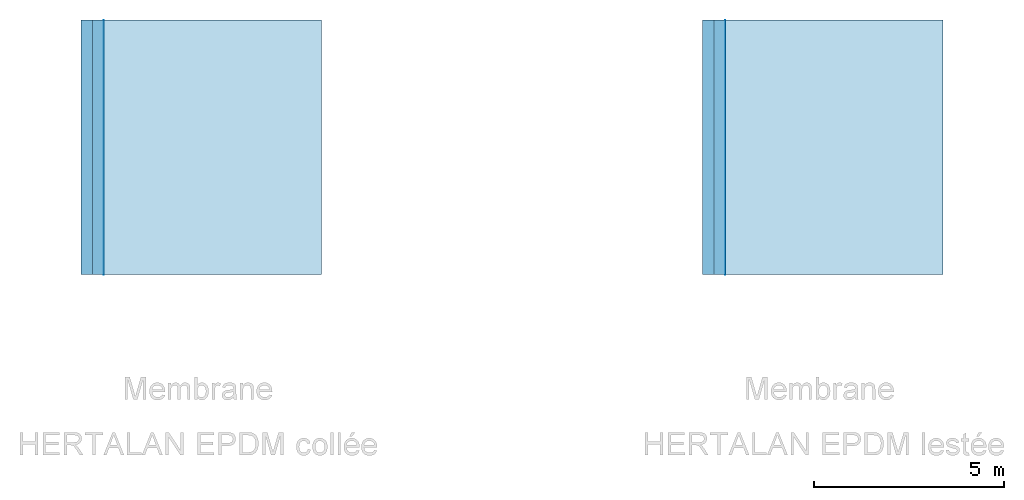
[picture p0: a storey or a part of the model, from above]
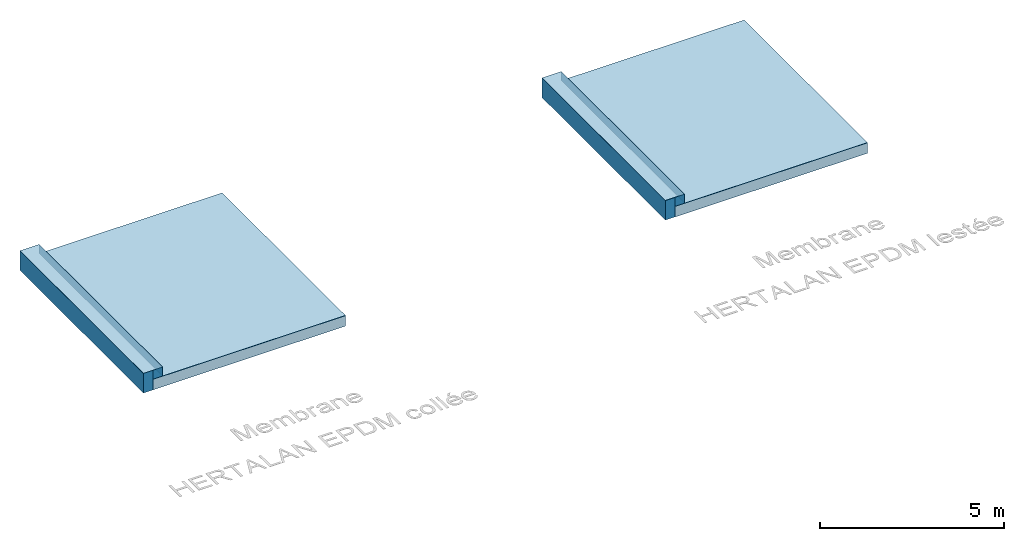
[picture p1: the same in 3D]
Properties of the parts of a building model (IFC2X3)

# File
Description: ViewDefinition [CoordinationView_V2.0, QuantityTakeOffAddOnView], RevitIdentifiers [ContentGUID: ba8bcfdc-dbaa-49fa-ac56-a6aa088a99af, VersionGUID: 4220247d-e962-4ae2-bb4a-8a5d9daa6820, NumberOfSaves: 104], CoordinateReference [CoordinateBase: Coordonnées partagées, ProjectSite: Interne]
File name: FR_Toit_VMBSO_HERTALAN_MEMBRANE_EPDM.ifc
Time: 2026-10-01T14:22:01+01:00
Written by: ODA SDAI 25.12
Made in: Autodesk - Revit 26.4.0.32 (FRA) - 26.4.0.32

# IfcSite, Default
RefLatitude: 42, 24, 53, 508911; RefLongitude: -71, -15, -29, -58837; RefElevation: 0 mm
Autre - Catégorie: Informations sur le projet

# IfcBuilding
Pset_BuildingCommon - NumberOfStoreys: 1
Autre - Catégorie: Informations sur le projet

# IfcBuildingStorey, Niveau 1
LongName: Niveau 1; Elevation: 0 mm
Autre - Catégorie: Niveaux; Famille: Niveau; Famille et type: Niveau: Niveau 1; ID du type: 1520; Type: Niveau 1
Contraintes - Elévation: 0 mm
Cotes - Hauteur de calcul: 0 mm
Données d'identification - Structure: no; Etage de bâtiment: yes; Nom: Niveau 1
Autre(Type) - Catégorie: Niveaux; Nom de la famille: Niveau
Contraintes(Type) - Référence de l'élévation: Point de base du projet
Graphismes(Type) - Couleur: 0; Epaisseur des lignes: 1; Motif des lignes: Plein; Valeur par défaut du symbole à l'extrémité 1: no; Valeur par défaut du symbole à l'extrémité 2: yes
Données d'identification(Type) - Nom du type: Niveau 1

# IfcBuildingElementProxy: Texte 3D:Model Text 1 (2)
In: Niveau 1
Type - Autre - Catégorie: Modèles génériques; Nom de la famille: Texte 3D
Type - Données d'identification - Nom du type: Model Text 1
Type - Texte - Gras: no; Italique: no; Police de texte: Arial; Taille du texte: 600 mm
Pset_BuildingElementProxyCommon - Reference: Model Text 1; sets with these values: 2
Autre - Famille: Texte 3D; Famille et type: Texte 3D: Model Text 1; ID du type: 2370; Type: Model Text 1
Contraintes - Plan de construction: <non associé>
Cotes - Profondeur: 10 mm
Graphismes - Alignement horizontal: Centre
Données d'identification - Sous-catégorie: Modèles génériques
Phase de construction - Phase de création: Nouvelle construction
Name (Texte 3D:Model Text 1:...) | Texte
24701 | Membrane HERTALAN EPDM collée
24706 | Membrane HERTALAN EPDM lestée

# IfcRoof (6)
In: Niveau 1
Pset_RoofCommon - IsExternal: yes
Autre - Catégorie: Toits; Famille: Toit de base
Contraintes - Décalage de la coupure: 0 mm; Lié au volume: no; Limite de pièce: yes; Niveau de base: Niveau 1
Construction - Coupe en chevron: Coupe verticale; Profondeur du bord de toiture: 0 mm
Phase de construction - Phase de création: Nouvelle construction
Name (Toit de base:...) | Material | Pset_QuantityTakeOff, Reference = Pset_RoofCommon, Reference = Type | ProjectedArea (m2) = TotalArea (m2) = GrossArea (m2) = NetArea (m2) = Surface (m2) | Famille et type | ID du type | Décalage inférieur à partir du niveau (mm) | Hauteur maximale de l'arrête (mm) | Epaisseur (mm) | Volume (m3)
Membrane Hertalan EPDM Partie courante collée:25614 | Membrane Hertalan EPDM collée_Partie courante 1.2 mm, Adhésif de contact 1.1 mm | Membrane Hertalan EPDM Partie courante collée | 38.5877 | Toit de base: Membrane Hertalan EPDM Partie courante collée | 13271 | 135.2 | 137.5 | 2.3 | 0.0887517 | Cotes - Inclinaison: 0
Membrane Hertalan EPDM Partie courante lestée:26349 | Film de protection polyester 0.8 mm, Membrane Hertalan EPDM lestée_Partie courante 1.5 mm | Membrane Hertalan EPDM Partie courante lestée | 38.5877 | Toit de base: Membrane Hertalan EPDM Partie courante lestée | 23930 | 135.2 | 137.5 | 2.3 | 0.0887517 | Cotes - Inclinaison: 0
Membrane Hertalan EPDM_Acrotère:31611 | Membrane Hertalan EPDM collée_Acrotère/Relevé 1.5 mm, Adhésif de contact 1.1 mm | Membrane Hertalan EPDM_Acrotère | 4.05083 | Toit de base: Membrane Hertalan EPDM_Acrotère | 19271 | 435.2 | 437.8 | 2.6 | 0.0105322 | Pset_ManufacturerTypeInformation - Manufacturer: VM BUILDING SOLUTIONS
Toit-Support autorisé:31936 | Isolation 100 mm, Pare vapeur 0.8 mm, Béton de pente 50 mm, Structure porteuse 200 mm | Toit-Support autorisé | 40.602 | Toit de base: Toit-Support autorisé | 31943 | -215.6 | 135.2 | 350.8 | 14.2432
Toit-Support autorisé:32010 | Isolation 100 mm, Pare vapeur 0.8 mm, Béton de pente 50 mm, Structure porteuse 200 mm | Toit-Support autorisé | 40.602 | Toit de base: Toit-Support autorisé | 31943 | -215.6 | 135.2 | 350.8 | 14.2432
Membrane Hertalan EPDM_Acrotère:32271 | Membrane Hertalan EPDM collée_Acrotère/Relevé 1.5 mm, Adhésif de contact 1.1 mm | Membrane Hertalan EPDM_Acrotère | 4.05083 | Toit de base: Membrane Hertalan EPDM_Acrotère | 19271 | 435.2 | 437.8 | 2.6 | 0.0105322 | Pset_ManufacturerTypeInformation - Manufacturer: VM BUILDING SOLUTIONS

# IfcSlab: Toit de base:Membrane Hertalan EPDM Partie courante collée, Toit de base:Membrane Hertalan EPDM Partie courante collée:25614
In: Niveau 1
Type - PredefinedType: ROOF
Type - Autre - Catégorie: Toits; Nom de la famille: Toit de base
Type - Construction - Climat: Zones de vent 1 à 4 (hors zone 5 et DROM)-Climat de plaine.; Conditions particulières: De faible à moyenne sur support bois. De faible à forte sur maçonnerie. Faible à très forte hygrométrie sur tôle d'acier nervurée.; Document de référence: DTA n°5.2/17-2578_V2, CCT Hertalan visé par Alpha Contrôle – Avril 2017; Epaisseur: 1,2 mm - 1,5 mm - 2,0 mm; Epaisseur par défaut: 2.3 mm; Masse surfacique: 1,47 kg/m² (1,2mm) - 1,84 kg/m² (1,5mm) - 2,46 kg/m² (2,0mm); Mise en œuvre: En adhérence totale ou partielle, existe en version pre-tape et en fixation mécanique; N° DTU: DTU de la série 43; Résistance au feu: Classe E Norme d'essai; Supports autorisés: Maçonnerie, Béton cellulaire, Bois et dérivés du bois, Isolation (laine minérale soudable, perlite expansée soudable, verre cellulaire, PIR, PUR, polystyrène…), Anciennes membranes bitumineuses; Type de toit: Nouvelle construction et rénovation, toiture accessible, technique ou non accessible de pente conforme à la norme NF P 84 série 200 (DTU série 43)
Type - Graphismes - Couleur vue détail faible: 0
Type - Données d'identification - Code Produit: E788; Commentaires du type: Membrane Hertalan EPDM collé; Description: Hertalan est une membrane EPDM non renforcée. Gamme moyenne.; Fournisseur: VM Building Solutions; Identifiant du type: Hertalan; Modèle: Membrane Hertalan EPDM collé; Nom du type: Membrane Hertalan EPDM Partie courante collée; URL: https://www.vmbuildingsolutions.com/fr-fr/epdm/membrane-epdm-hertalan
Type - Matériaux et finitions - Matériau principal: Membrane EPDM caoutchouc Hertalan
Type - Propriétés analytiques - Coefficient d'absorbance: 0.1; Rugosité: 1
Type - Pset_ReinforcementBarPitchOfSlab - Description: Hertalan est une membrane EPDM non renforcée. Gamme moyenne.
Material: Membrane Hertalan EPDM collée_Partie courante 1.2 mm, Adhésif de contact 1.1 mm
Pset_QuantityTakeOff - Reference: Membrane Hertalan EPDM Partie courante collée; sets with these values: 2
Pset_SlabCommon - Reference: Membrane Hertalan EPDM Partie courante collée; IsExternal: yes; PitchAngle: 0 deg
BaseQuantities - NetArea: 3.58491 m2; NetVolume: 0.0082453 m3; GrossArea: 38.5877 m2; GrossVolume: 0.0082453 m3; Perimeter: 24922.8 mm

# IfcSlab: Toit de base:Membrane Hertalan EPDM Partie courante lestée, Toit de base:Membrane Hertalan EPDM Partie courante lestée:26349
In: Niveau 1
Type - PredefinedType: ROOF
Type - Autre - Catégorie: Toits; Nom de la famille: Toit de base
Type - Construction - Conditions particulières: De faible à moyenne sur support bois. De faible à forte sur maçonnerie. Faible à très forte hygrométrie sur tôle d'acier nervurée.; Document de référence: DTA n°5.2/17-2578_V2, CCT Hertalan visé par Alpha Contrôle – Avril 2017; Epaisseur: 1,2 mm - 1,5 mm - 2,0 mm; Epaisseur par défaut: 2.3 mm; Masse surfacique: 1,47 kg/m² (1,2mm) - 1,84 kg/m² (1,5mm) - 2,46 kg/m² (2,0mm); Mise en œuvre: Adhérence totale ou partielle ou installation libre sous le lestage; N° DTU: DTU de la série 43; Résistance au feu: Classe E Norme d'essai; Supports autorisés: Maçonnerie, Béton cellulaire, Bois et dérivés du bois, Isolation (laine minérale soudable, perlite expansée soudable, verre cellulaire, PIR, PUR, polystyrène…), Anciennes membranes bitumineuses; Type de toit: Nouvelle construction et rénovation, toiture accessible, technique ou non accessible de pente conforme à la norme NF P 84 série 200 (DTU série 43), ou avis technique du support. En construction neuve ou en rénovation
Type - Graphismes - Couleur vue détail faible: 0
Type - Données d'identification - Code Produit: E788; Commentaires du type: Membrane EPDM Hertalan lestée; Description: Hertalan est une membrane EPDM non renforcée. Gamme moyenne.; Fournisseur: VM Building Solutions; Identifiant du type: Hertalan; Modèle: Membrane EPDM Hertalan lestée; Nom du type: Membrane Hertalan EPDM Partie courante lestée; URL: https://www.vmbuildingsolutions.com/fr-fr/epdm/membrane-epdm-hertalan
Type - Matériaux et finitions - Matériau principal: Membrane EPDM caoutchouc Hertalan
Type - Propriétés analytiques - Coefficient d'absorbance: 0.1; Rugosité: 1
Type - Pset_ReinforcementBarPitchOfSlab - Description: Hertalan est une membrane EPDM non renforcée. Gamme moyenne.
Material: Film de protection polyester 0.8 mm, Membrane Hertalan EPDM lestée_Partie courante 1.5 mm
Pset_QuantityTakeOff - Reference: Membrane Hertalan EPDM Partie courante lestée; sets with these values: 2
Pset_SlabCommon - IsExternal: yes; PitchAngle: 0 deg; Reference: Membrane Hertalan EPDM Partie courante lestée
BaseQuantities - NetArea: 3.58491 m2; NetVolume: 0.0082453 m3; GrossArea: 38.5877 m2; GrossVolume: 0.0082453 m3; Perimeter: 24922.8 mm

# IfcSlab: Toit de base:Membrane Hertalan EPDM_Acrotère (2)
In: Niveau 1
Type - PredefinedType: ROOF
Type - Autre - Catégorie: Toits; Nom de la famille: Toit de base
Type - Construction - Conditions particulières: De faible à moyenne sur support bois. De faible à forte sur maçonnerie. Faible à très forte hygrométrie sur tôle d'acier nervurée.; Document de référence: DTA n°5.2/17-2578_V2, CCT Hertalan visé par Alpha Contrôle – Avril 2017; Epaisseur: 1,2 mm - 1,5 mm - 2,0 mm; Epaisseur par défaut: 2.6 mm; Masse surfacique: 1,47 kg/m² (1,2mm) _ 1,84 kg/m² (1,5mm) _ 2,46 kg/m² (2,0mm); Mise en œuvre: Adhérence totale ou partielle ou installation libre sous le lestage; N° DTU: DTU de la série 43; Supports autorisés: Maçonnerie, Béton cellulaire, Bois et dérivés du bois, Isolation (laine minérale soudable (1), perlite expansée soudable (2), verre cellulaire, PIR, PUR, polystyrène…), Anciennes membranes bitumineuses; Type de toit: Nouvelle construction et rénovation, toiture accessible, technique ou non accessible de pente conforme à la norme NF P 84 série 200 (DTU série 43)
Type - Graphismes - Couleur vue détail faible: 0
Type - Données d'identification - Description: Hertalan est une membrane EPDM non renforcée. Gamme moyenne. Hertalan flashing – Bande EPDM non vulcanisée autoadhésive déformable pour finitions. Coins intérieur et extérieur Hertalan préfabriqués. Colles KS 137, KS 143, KS 205 et KS 96; Fabricant: VM BUILDING SOLUTIONS; Fournisseur: VM Building Solutions; Identifiant du type: Hertalan; Modèle: Membrane Hertalan EPDM collé; Nom du type: Membrane Hertalan EPDM_Acrotère; Note d'identification: Membrane Hertalan EPDM collée; URL: https://www.vmbuildingsolutions.com/fr-fr/epdm/membrane-epdm-hertalan
Type - Matériaux et finitions - Matériau principal: Membrane EPDM caoutchouc Hertalan
Type - Propriétés analytiques - Coefficient d'absorbance: 0.1; Rugosité: 1
Type - Pset_ManufacturerTypeInformation - Manufacturer: VM BUILDING SOLUTIONS
Type - Pset_ReinforcementBarPitchOfSlab - Description: Hertalan est une membrane EPDM non renforcée. Gamme moyenne. Hertalan flashing – Bande EPDM non vulcanisée autoadhésive déformable pour finitions. Coins intérieur et extérieur Hertalan préfabriqués. Colles KS 137, KS 143, KS 205 et KS 96
Material: Membrane Hertalan EPDM collée_Acrotère/Relevé 1.5 mm, Adhésif de contact 1.1 mm
Pset_QuantityTakeOff - Reference: Membrane Hertalan EPDM_Acrotère; sets with these values: 2
Pset_SlabCommon - IsExternal: yes; PitchAngle: 0 deg; Reference: Membrane Hertalan EPDM_Acrotère
BaseQuantities - NetArea: 0.376335 m2; NetVolume: 0.000978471 m3; GrossArea: 4.05083 m2; GrossVolume: 0.000978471 m3; Perimeter: 14635.5 mm
Name (Toit de base:Membrane Hertalan EPDM_Acrotère:...)
31611
32271

# IfcSlab: Toit de base:Toit-Support autorisé (2)
In: Niveau 1
Type - PredefinedType: ROOF
Type - Autre - Catégorie: Toits; Nom de la famille: Toit de base
Type - Construction - Epaisseur par défaut: 350.8 mm
Type - Graphismes - Couleur vue détail faible: 0
Type - Données d'identification - Nom du type: Toit-Support autorisé
Type - Propriétés analytiques - Coefficient d'absorbance: 0.1; Rugosité: 1
Material: Isolation 100 mm, Pare vapeur 0.8 mm, Béton de pente 50 mm, Structure porteuse 200 mm
Pset_QuantityTakeOff - Reference: Toit-Support autorisé; sets with these values: 2
Pset_SlabCommon - IsExternal: yes; PitchAngle: 0 deg; Reference: Toit-Support autorisé
BaseQuantities - NetArea: 3.77205 m2; NetVolume: 1.32324 m3; GrossArea: 40.602 m2; GrossVolume: 1.32324 m3; Perimeter: 25522.8 mm
Name (Toit de base:Toit-Support autorisé:...)
31936
32010

# IfcWallStandardCase: Mur de base:Membrane Hertalan EPDM Relevé collé (2)
In: Niveau 1
Type - PredefinedType: STANDARD; Material: Membrane Hertalan EPDM collée_Acrotère/Relevé 1.5 mm, Adhésif de contact 1.1 mm
Type - Autre - Catégorie: Murs; Nom de la famille: Mur de base
Type - Construction - Fonction: Extérieur; Retournement aux extrémités: Aucun(e); Retournement aux insertions: Ne pas retourner; Climat: Zones de vent 1 à 4 (hors zone 5 et DROM)-Climat de plaine.; Conditions particulières: Adhérence totale; Largeur: 2.6 mm; Mise en œuvre: Le relevé est entièrement recouvert de Hertalan collé à l'aide de l'adhésif de contact KS137 ou KS205.; N° DTU: DTU de la série 43; Supports autorisés: Maçonnerie, Béton cellulaire, Bois et dérivés du bois, Isolation (laine minérale soudable (1), perlite expansée soudable (2), verre cellulaire, PIR, PUR, polystyrène…), Anciennes membranes bitumineuses; Type de toit: Nouvelle construction et rénovation, toiture accessible, technique ou non accessible de pente conforme à la norme NF P 84 série 200 (DTU série 43)
Type - Graphismes - Couleur vue détail faible: 0
Type - Données d'identification - Commentaires du type: Membrane EPDM Hertalan collé; Description: Mise en place rapide sans plis. Très haute résistance constante aux UV. 100 % étanche pendant 50 ans. Pose sans flamme Très haute résistance constante aux UV 100 % étanche pendant 50 ans Pose sans flamme; Fournisseur: VM Building Solutions; Identifiant du type: Hertalan; Modèle: Membrane EPDM Hertalan collé; Nom du type: Membrane Hertalan EPDM Relevé collé; URL: https://www.vmbuildingsolutions.com/fr-fr/epdm/membrane-epdm-hertalan
Type - Matériaux et finitions - Matériau principal: Membrane EPDM caoutchouc Hertalan
Type - Propriétés analytiques - Coefficient d'absorbance: 0.1; Rugosité: 1
Type - Pset_ReinforcementBarPitchOfWall - Description: Mise en place rapide sans plis. Très haute résistance constante aux UV. 100 % étanche pendant 50 ans. Pose sans flamme Très haute résistance constante aux UV 100 % étanche pendant 50 ans Pose sans flamme
BaseQuantities - Length: 6714.46 mm; Width: 2.6 mm; GrossFootprintArea: 0.0174576 m2
Pset_QuantityTakeOff - Reference: Membrane Hertalan EPDM Relevé collé; sets with these values: 2
Pset_WallCommon - IsExternal: yes; ExtendToStructure: no; LoadBearing: no; Reference: Membrane Hertalan EPDM Relevé collé
Autre - Famille: Mur de base; Famille et type: Mur de base: Membrane Hertalan EPDM Relevé collé; ID du type: 2373; Type: Membrane Hertalan EPDM Relevé collé
Contraintes - Lié au volume: no; Limite de pièce: yes; Contrainte inférieure: Niveau 1; Décalage supérieur: 0 mm; Extension inférieure: 0 mm; Extension supérieure: 0 mm; Ligne de justification: Axe du mur; Partie inférieure attachée: no; Partie supérieure attachée: no
Cotes - Longueur: 6714.46 mm
Phase de construction - Phase de création: Nouvelle construction
Structure - Structure: no; Utilisation structurelle: Non porteur
Définition de la coupe transversale - Coupe transversale: Vertical
Name (Mur de base:Membrane Hertalan EPDM Relevé collé:...) | Height (mm) | GrossVolume (m3) = NetVolume (m3) = Volume (m3) | GrossSideArea (m2) = NetSideArea (m2) = Surface (m2) | Décalage inférieur (mm) | Hauteur non contrainte (mm)
25628 | 296.7 | 0.00517967 | 1.99218 | 138.5 | 161.5
26363 | 297 | 0.00518491 | 1.9942 | 178.665 | 121.335

# IfcWallStandardCase: Mur de base:Mur 1 (4)
In: Niveau 1
Type - PredefinedType: STANDARD; Material: Isolation 100 mm, Maçonnerie ascendante 200 mm
Type - Autre - Catégorie: Murs; Nom de la famille: Mur de base
Type - Construction - Fonction: Extérieur; Largeur: 300 mm; Retournement aux extrémités: Aucun(e); Retournement aux insertions: Ne pas retourner
Type - Graphismes - Couleur vue détail faible: 0
Type - Données d'identification - Nom du type: Mur 1
Type - Propriétés analytiques - Coefficient d'absorbance: 0.1; Rugosité: 1
BaseQuantities - Length: 6714.46 mm; Width: 300 mm; GrossFootprintArea: 2.01434 m2
Pset_QuantityTakeOff - Reference: Mur 1; sets with these values: 2
Pset_WallCommon - IsExternal: yes; Reference: Mur 1; ExtendToStructure: no; LoadBearing: no
Autre - Famille: Mur de base; Famille et type: Mur de base: Mur 1; ID du type: 1557; Type: Mur 1
Contraintes - Lié au volume: no; Limite de pièce: yes; Contrainte inférieure: Niveau 1; Décalage supérieur: 0 mm; Extension inférieure: 0 mm; Extension supérieure: 0 mm; Ligne de justification: Axe du mur; Partie inférieure attachée: no; Partie supérieure attachée: no
Cotes - Longueur: 6714.46 mm
Phase de construction - Phase de création: Nouvelle construction
Structure - Structure: no; Utilisation structurelle: Non porteur
Définition de la coupe transversale - Coupe transversale: Vertical
Name (Mur de base:Mur 1:...) | Height (mm) = Hauteur non contrainte (mm) | GrossVolume (m3) = NetVolume (m3) = Volume (m3) | GrossSideArea (m2) = NetSideArea (m2) = Surface (m2) | Décalage inférieur (mm)
25626 | 650.8 | 1.31093 | 4.36977 | -215.6
25627 | 300 | 0.604302 | 2.01434 | 0
26361 | 650.8 | 1.31093 | 4.36977 | -215.6
26362 | 300 | 0.604302 | 2.01434 | 0
